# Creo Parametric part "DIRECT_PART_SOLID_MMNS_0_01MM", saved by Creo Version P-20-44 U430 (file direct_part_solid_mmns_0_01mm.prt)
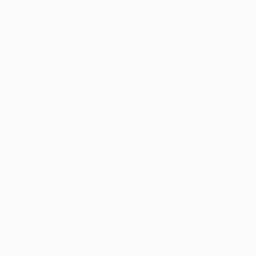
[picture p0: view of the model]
Units: millimeter Newton Second (mmNs); MM, TONNE, SECS

Created from: INLBS_PART_SOLID.PRT

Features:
  1. datum plane "RIGHT"
  2. datum plane "TOP"
  3. datum plane "FRONT"
  4. coordinate system

Surfaces: 3 plane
